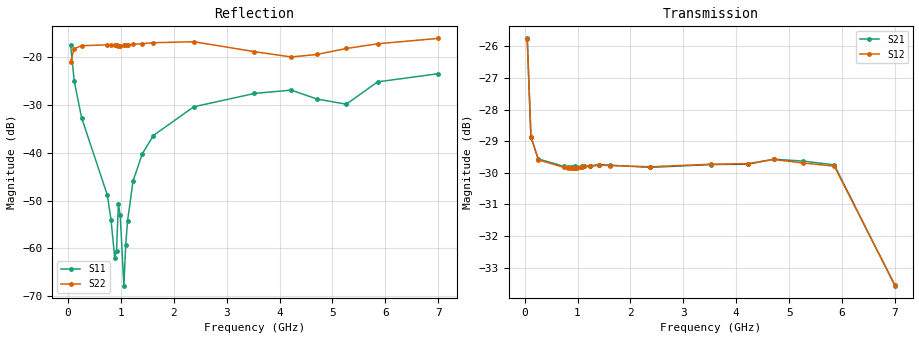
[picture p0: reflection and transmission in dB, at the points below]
! Integrated Device Technology
! Corporate Headquarters
! 6024 Silver Creek Valley Road
! San Jose, CA 95138  USA
! Phone:  1-408-284-8200
! Toll Free:  1-800-223-1366
! Webpage:  http://www.idt.com/
! Timing and RF Division
! 515 Groton Road, Suite 102
! Westford, MA 01886-6024
! Device:  F2258
! Description: Voltage Variable RF Attenuator
! Frequency:  50.0 -  6000.00 MHz
! Package:  3x3 mm Thin QFN Plastic Package: 16 pin
! Ports:  2 RF, 2 DC
!  Pin  1  = NC
!  Pin  2  = NC
!  Pin  3  = RF2  = Port 2
!  Pin  4  = GND
!  Pin  5  = Vdd
!  Pin  6  = NC
!  Pin  7  = VCTRL
!  Pin  8  = NC
!  Pin  9  = GND
!  Pin 10  = RF1  = Port 1
!  Pin 11  = NC
!  Pin 12  = NC
!  Pin 13  = NC
!  Pin 14  = NC
!  Pin 15  = NC
!  Pin 16  = NC
! Vcntrl:  1.660 Volts
! Vdd:  +3.300 Volts
! Current:  1.159 mA
! Data:  The device was measured on a the F2258 evaluation board which has
!  individual transmission lines to the RF pins.  Data was collected
!  using a calibrated network analyzer.  The evaluation board was
!  de-embedded using a TRL calibration technique.
!  The reference plane is the edge of the package pin.
! Misc:  SN 10
!  Action Tracker AT0285
! Date Measured:  2014-12-10
! Date:  2016-01-13  MJV
! Note:
!  Integrated Device Technology supplies this data as a sample of measured
!  data at the package pin for this product.  Your particular data for this
!  product may vary.
!  Data was taken at 25 degrees C.
!  Integrated Device Technology reserves the right to change this data at anytime.
!Freq_(GHz)  S11M_(dB)  S11P_(deg)  S21M_(dB)  S21P_(deg)  S12M_(dB)  S12P_(deg)  S22M_(dB)  S22P_(deg)
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# GHz S dB R 50
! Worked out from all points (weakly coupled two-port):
!   201 points, 50 MHz to 7 GHz, reference 50 ohm
!   highest |S21| = -25.75 dB at 50 MHz (marker M1); lowest = -33.6 dB at 7 GHz (marker M2)
!   lowest |S11| = -67.8 dB at 1.058 GHz (marker M3), VSWR 1.00, Z = 50 + j0.00434 ohm
!   |S11| at or under -10 dB: start of sweep to end of sweep
!   |S22| runs from -21.0 to -16.2 dB; largest |S21 - S12| = 0.00032
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0.05  -17.53 -109.9  -25.75 -49.9  -25.78 -50.0  -21.01 -40.8
0.1195  -25.12 -104.9  -28.86 -26.8  -28.86 -26.8  -18.32 -11.8
0.2585  -32.72 -107.7  -29.56 -14.8  -29.59 -14.8  -17.71 -7.0
0.745  -48.88 -122.7  -29.80 -10.8  -29.83 -10.8  -17.53 -9.8
0.8145  -54.03 -132.2  -29.82 -10.9  -29.84 -10.9  -17.53 -10.5
0.884  -61.91 170.3  -29.83 -11.1  -29.86 -11.1  -17.57 -11.7
0.91875  -60.46 127.8  -29.82 -11.3  -29.84 -11.3  -17.57 -12.2
0.9535  -50.69 -144.3  -29.80 -11.4  -29.85 -11.4  -17.77 -11.7
0.98825  -53.10 -157.6  -29.81 -11.5  -29.84 -11.5  -17.75 -12.5
1.05775  -67.76 6.1  -29.81 -11.8  -29.82 -11.8  -17.63 -13.2
1.0925  -59.21 32.7  -29.80 -12.0  -29.81 -12.0  -17.61 -13.6
1.12725  -54.21 41.1  -29.79 -12.1  -29.80 -12.1  -17.55 -14.1
1.2315  -45.91 29.3  -29.78 -12.8  -29.80 -12.8  -17.43 -15.2
1.40525  -40.27 25.5  -29.74 -14.2  -29.76 -14.2  -17.29 -16.8
1.61375  -36.45 27.4  -29.76 -15.9  -29.77 -15.9  -17.09 -19.3
2.37825  -30.45 45.1  -29.83 -22.0  -29.81 -22.0  -16.88 -26.6
3.525  -27.67 90.2  -29.74 -32.0  -29.73 -32.0  -18.95 -43.3
4.22  -26.97 104.6  -29.73 -38.5  -29.71 -38.5  -20.06 -60.7
4.7065  -28.83 94.8  -29.57 -43.6  -29.58 -43.5  -19.54 -69.1
5.2625  -29.91 52.1  -29.63 -49.8  -29.69 -49.7  -18.29 -71.3
5.85325  -25.25 28.5  -29.75 -58.4  -29.79 -58.3  -17.31 -71.4
7  -23.55 83.8  -33.57 -71.7  -33.56 -71.7  -16.18 -129.7
